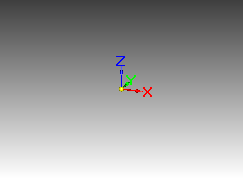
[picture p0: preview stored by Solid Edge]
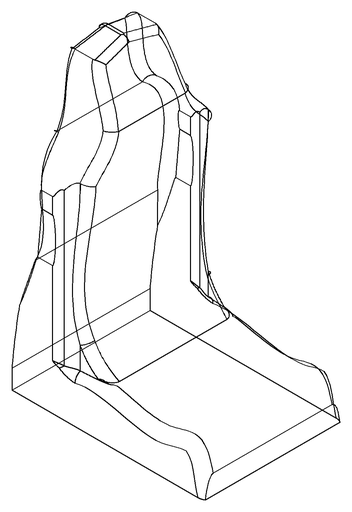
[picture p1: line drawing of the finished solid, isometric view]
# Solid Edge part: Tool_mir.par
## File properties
Author: Türk
Template: iso part.par
Last saved by: Türk
Revision: 2
Application: Solid Edge
Accuracy: 0,990
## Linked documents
Tool.par
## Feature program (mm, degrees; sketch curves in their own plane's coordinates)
part copy "CopiedPart_1"
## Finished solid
Body 1: solid body, 51 faces, 155 edges, 106 vertices.
  Faces by surface: blend 18, swept 17, plane 9, cylinder 2, spline 2, torus 2, sphere 1
  Edges by curve: intersection 78, curve on surface 34, line 32, circle 9, spline 2
Bounding box of the edges (mm; curved faces can reach further): 360.311 x 500.000 x 769.640, from (166.0829, -2182.0301, -25) to (526.3939, -1682.0301, 744.6402).
Cylindrical faces by radius (mm): R20.6875 x1, R772.185 x1
Toroidal faces (ring radius, tube radius in mm): R75 r25 x2
Spherical faces by radius (mm): R20.6875 x1
Planar faces by outward normal: +x 2, +y 1, -x 2, -y 1, -z 1, oblique 2
